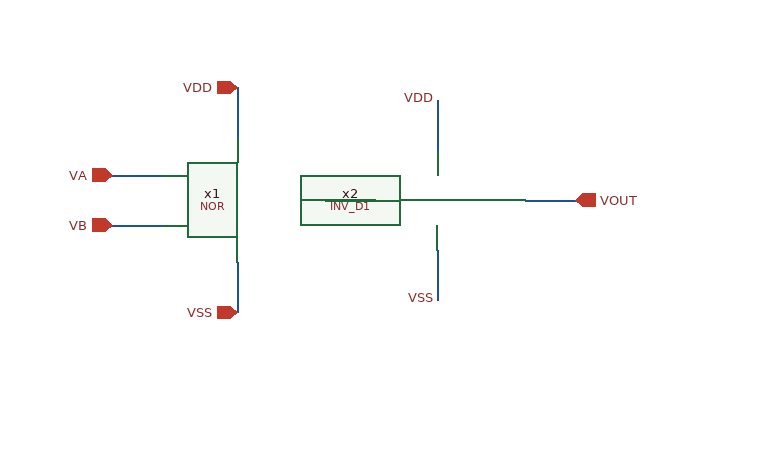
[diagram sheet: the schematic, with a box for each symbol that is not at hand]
v {xschem version=3.4.8RC file_version=1.2}
G {}
K {}
V {}
S {}
F {}
E {}
N 160 -370 160 -330 {lab=VDD}
N 160 -230 160 -190 {lab=VSS}
N 60 -300 100 -300 {lab=VA}
N 60 -260 100 -260 {lab=VB}
N 390 -280 430 -280 {lab=VOUT}
N 230 -280 270 -280 {lab=#net1}
N 320 -360 320 -320 {lab=VDD}
N 320 -240 320 -200 {lab=VSS}
C {iopin.sym} 160 -370 0 0 {name=p1 lab=VDD}
C {iopin.sym} 160 -190 0 0 {name=p2 lab=VSS}
C {ipin.sym} 60 -300 0 0 {name=p3 lab=VA}
C {ipin.sym} 60 -260 0 0 {name=p4 lab=VB}
C {opin.sym} 430 -280 0 0 {name=p5 lab=VOUT}
C {INV_D1.sym} 230 -140 0 0 {name=x2}
C {NOR.sym} 80 -160 0 0 {name=x1}
C {lab_wire.sym} 320 -360 0 0 {name=p6 lab=VDD}
C {lab_wire.sym} 320 -200 0 0 {name=p7 lab=VSS}
